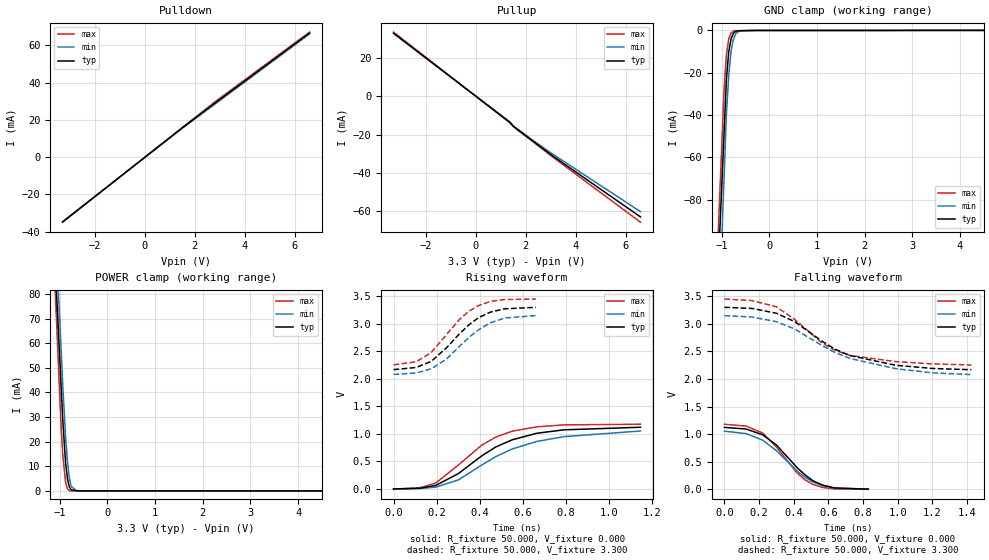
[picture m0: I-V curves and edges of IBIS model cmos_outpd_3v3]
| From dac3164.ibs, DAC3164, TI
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[Model]   cmos_outpd_3v3
Model_type 3-state
Vref=0.000E+00
Rref=1.000E+06
Cref=0.000E+00
Vmeas=1.650E+00
C_comp   1.070E-12   1.070E-12   1.070E-12
[Voltage Range]   3.300E+00   3.150E+00   3.450E+00
[POWER Clamp Reference]   3.300E+00   3.150E+00   3.450E+00
[GND Clamp Reference]   0.000E+00   0.000E+00   0.000E+00
[Pullup Reference]   3.300E+00   3.150E+00   3.450E+00
[Pulldown Reference]   0.000E+00   0.000E+00   0.000E+00
[Temperature Range]   25   85   -40
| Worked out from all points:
|   slope of the pulldown table from 0 to 0.495 V, typ, clamps not added: 95.4 ohm
|   slope of the pullup table from 0 to 0.495 V, typ, clamps not added: 100 ohm
|   GND clamp passes 1 mA (typ) near -0.74 V on its own axis
|   POWER clamp passes 1 mA (typ) near -0.78 V on its own axis
|   rising waveform, R_fixture 50.000, V_fixture 0.000: 20-80 % time 273ps typ, 321ps min, 229ps max; typ from 0 V to 1.12 V
|   falling waveform, R_fixture 50.000, V_fixture 0.000: 20-80 % time 214ps typ, 223ps min, 189ps max; typ from 1.12 V to 0 V
|   rising waveform, R_fixture 50.000, V_fixture 3.300: 20-80 % time 178ps typ, 188ps min, 165ps max; typ from 2.17 V to 3.3 V
|   falling waveform, R_fixture 50.000, V_fixture 3.300: 20-80 % time 365ps typ, 424ps min, 305ps max; typ from 3.3 V to 2.17 V
[GND Clamp]
-3.3V     -1.265A    -1.499A    -1.32A
-950mV    -49.06mA   -70.33mA   -28.61mA
-900mV    -23.2mA    -39.94mA   -11.61mA
-850mV    -9.95mA    -20.84mA   -3.839mA
-800mV    -3.735mA   -9.456mA   -1.133mA
-750mV    -1.255mA   -3.879mA   -337.2uA
-700mV    -399.4uA   -1.494mA   -148.9uA
-650mV    -154.5uA   -584.3uA   -131.2uA
-600mV    -133.2uA   -198.5uA   -113.5uA
-300mV    -15.44uA   -31.58uA   -24.54uA
6.6V      32.89uA    44.03uA    40.1uA
[Power Clamp]
-3.3V     957.2mA    1.007A     1.073A
-1.1V     92.68mA    109.2mA    82.9mA
-1.06V    76.96mA    92.93mA    65.21mA
-1.04V    69.1mA     84.79mA    56.18mA
-980mV    45.39mA    60.51mA    28.92mA
-940mV    29.43mA    43.6mA     15.23mA
-880mV    11.72mA    22.38mA    3.527mA
-840mV    5.021mA    12.01mA    880.7uA
-800mV    1.611mA    5.206mA    167.9uA
-760mV    445uA      1.789mA    28uA
-640mV    29.31uA    9.511uA    16.77uA
6.6V      0A         0A         0A
[Pullup]
-3.3V     33mA       32.76mA    33.52mA
1.36V     -13.56mA   -13.33mA   -13.75mA
1.52V     -15.88mA   -15.57mA   -15.97mA
2.42V     -24.71mA   -24.19mA   -25mA
3.08V     -31.11mA   -30.16mA   -31.67mA
6.6V      -62.94mA   -60.21mA   -65.7mA
[Pulldown]
-3.3V     -34.84mA   -34.69mA   -34.99mA
1.48V     15.55mA    15.35mA    15.69mA
2.82V     29.19mA    28.62mA    29.86mA
6.6V      66.72mA    66.24mA    67.21mA
[Rising Waveform]
R_fixture = 50.000
V_fixture = 0.000
V_fixture_min = 0.000
V_fixture_max = 0.000
|  time   V(typ)   V(min)   V(max)
0s        435.7uV    927.3uV    -4.246mV
120ps     11.99mV    6.341mV    19.28mV
195ps     62.56mV    32.43mV    104.3mV
300ps     277.3mV    163.1mV    433mV
410ps     604.1mV    437.5mV    798.5mV
475ps     764.1mV    587.5mV    943.7mV
550ps     892.5mV    726.3mV    1.049V
665ps     1.012V     863.7mV    1.129V
790ps     1.074V     950.1mV    1.164V
1.145ns   1.121V     1.053V     1.176V
[Falling Waveform]
R_fixture = 50.000
V_fixture = 0.000
V_fixture_min = 0.000
V_fixture_max = 0.000
|  time   V(typ)   V(min)   V(max)
0s        1.121V     1.053V     1.179V
125ps     1.092V     1.009V     1.145V
220ps     987.8mV    891.2mV    1.02V
300ps     801.4mV    699.1mV    765.1mV
420ps     388.6mV    328mV      291.6mV
465ps     259.3mV    216mV      169.1mV
510ps     154mV      133.5mV    88.15mV
565ps     75.22mV    64.94mV    32.04mV
635ps     22.94mV    19.9mV     4.413mV
830ps     435.7uV    927.3uV    708.3uV
[Rising Waveform]
R_fixture = 50.000
V_fixture = 3.300
V_fixture_min = 3.150
V_fixture_max = 3.450
|  time   V(typ)   V(min)   V(max)
0s        2.168V     2.08V      2.255V
105ps     2.207V     2.107V     2.31V
175ps     2.318V     2.183V     2.479V
245ps     2.562V     2.359V     2.802V
305ps     2.816V     2.587V     3.077V
350ps     2.984V     2.755V     3.23V
395ps     3.114V     2.894V     3.334V
450ps     3.214V     3.02V      3.408V
515ps     3.273V     3.105V     3.442V
660ps     3.3V       3.15V      3.45V
[Falling Waveform]
R_fixture = 50.000
V_fixture = 3.300
V_fixture_min = 3.150
V_fixture_max = 3.450
|  time   V(typ)   V(min)   V(max)
0s        3.3V       3.15V      3.45V
160ps     3.28V      3.124V     3.422V
300ps     3.192V     3.039V     3.309V
405ps     3.041V     2.908V     3.083V
565ps     2.681V     2.602V     2.648V
640ps     2.537V     2.477V     2.519V
725ps     2.424V     2.372V     2.427V
990ps     2.248V     2.186V     2.315V
1.205ns   2.19V      2.109V     2.272V
1.425ns   2.168V     2.08V      2.255V
[Ramp]
dV/dt_r   6.7298E-01/2.7256E-10   6.2996E-01/3.2059E-10   7.0820E-01/2.2857E-10
dV/dt_f   6.7918E-01/3.6465E-10   6.4206E-01/4.2404E-10   7.1696E-01/3.0414E-10
R_load = 50
